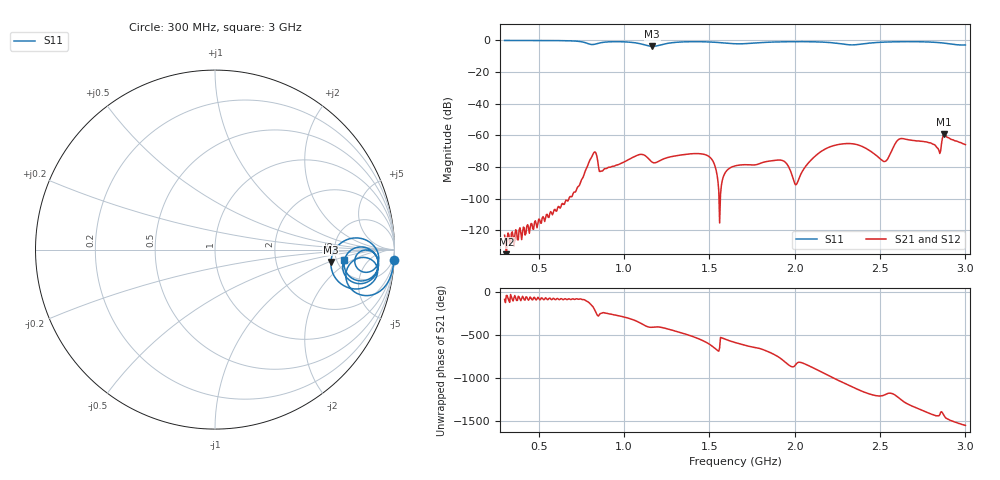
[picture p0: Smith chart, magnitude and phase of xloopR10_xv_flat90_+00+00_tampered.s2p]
! xloopR10_xv_flat90_+00+00_tampered, gap C 0.80 pF
! simulated by sim/fixtures_fdtd.py (S12 = S21, S22 not computed)
# HZ S RI R 50
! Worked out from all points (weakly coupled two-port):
!   541 points, 300 MHz to 3 GHz, reference 50 ohm
!   highest |S21| = -59.33 dB at 2.875 GHz (marker M1); lowest = -137.0 dB at 310 MHz (marker M2)
!   lowest |S11| = -3.8 dB at 1.165 GHz (marker M3), VSWR 4.70, Z = 222 - j52.9 ohm
!   |S11| at or under -10 dB: nowhere
!   |S22| runs from - to - dB; largest |S21 - S12| = 0
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3e8  0.9974 -0.0578  -0 -7e-07  -0 -7e-07  0 0
3.1e8  0.9972 -0.06  1e-07 -1e-07  1e-07 -1e-07  0 0
7.5e8  0.8743 -0.2526  1.4e-06 -3.89e-05  1.4e-06 -3.89e-05  0 0
7.8e8  0.7896 -0.2434  -3.01e-05 -8.64e-05  -3.01e-05 -8.64e-05  0 0
8.25e8  0.7477 -0.085  -0.000276 0.000101  -0.000276 0.000101  0 0
8.6e8  0.8383 -0.0444  -1.88e-05 6.98e-05  -1.88e-05 6.98e-05  0 0
1.095e9  0.7552 -0.2157  0.00025 -1.66e-05  0.00025 -1.66e-05  0 0
1.165e9  0.6456 -0.0689  8.56e-05 -0.000114  8.56e-05 -0.000114  0 0
1.2e9  0.69 0.0267  9.75e-05 -0.000113  9.75e-05 -0.000113  0 0
1.44e9  0.9098 -0.071  -0.000262 4.19e-05  -0.000262 4.19e-05  0 0
1.545e9  0.859 -0.1245  4.13e-05 3.74e-05  4.13e-05 3.74e-05  0 0
1.65e9  0.7812 -0.082  -7.03e-05 8.28e-05  -7.03e-05 8.28e-05  0 0
1.91e9  0.9001 -0.0371  0.000119 -0.000116  0.000119 -0.000116  0 0
2.05e9  0.9091 -0.0992  -2.88e-05 -7.65e-05  -2.88e-05 -7.65e-05  0 0
2.1e9  0.8999 -0.1236  -0.00016 -7.18e-05  -0.00016 -7.18e-05  0 0
2.305e9  0.7282 -0.1201  0.00055 4.95e-05  0.00055 4.95e-05  0 0
2.52e9  0.8839 -0.0162  -8.25e-05 -0.000127  -8.25e-05 -0.000127  0 0
2.55e9  0.8955 -0.0317  -2.95e-05 -0.000202  -2.95e-05 -0.000202  0 0
2.615e9  0.9084 -0.0661  -0.000736 -0.000238  -0.000736 -0.000238  0 0
2.845e9  0.8346 -0.1859  0.000336 1.8e-06  0.000336 1.8e-06  0 0
2.875e9  0.8017 -0.1898  0.00108 3.45e-05  0.00108 3.45e-05  0 0
3e9  0.7184 -0.0592  -0.00019 -0.000477  -0.00019 -0.000477  0 0
